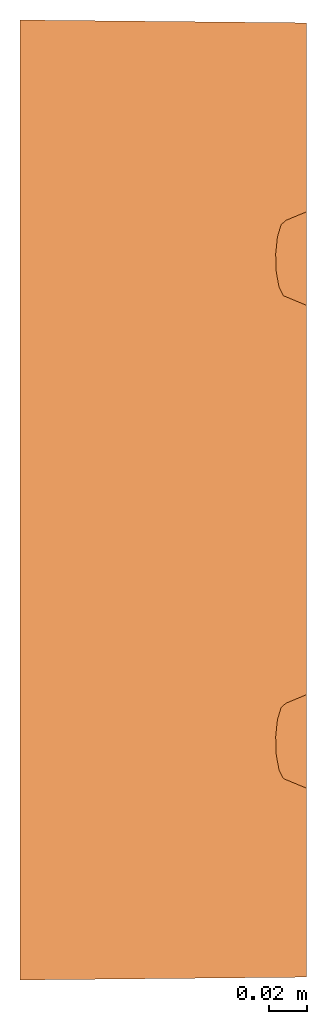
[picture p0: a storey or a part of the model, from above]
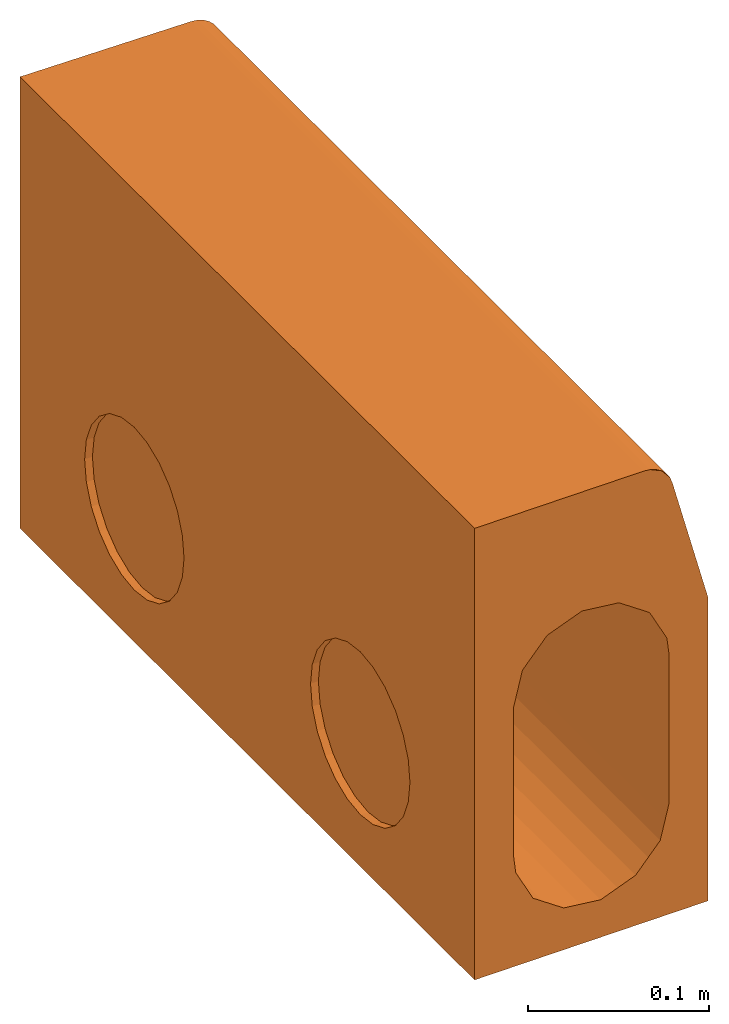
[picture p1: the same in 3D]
Properties of the parts of a building model (IFC2X3)

# File
Description: ViewDefinition [CoordinationView]
File name: 7971 - 25-11m internal mitre.ifc
Time: 2013-09-12T12:57:43
Written by: Autodesk Revit 2013
Made in: 20120221_2030(x64)

# IfcProject, Project Number
LongName: Project Name; Phase: Project Status

# IfcSite, Default
RefLatitude: 42, 21, 30, 344238; RefLongitude: -71, -3, -35, -194702; RefElevation: 0 mm

# IfcBuilding
Pset_BuildingCommon - NumberOfStoreys: 2
Other - Project Address: Enter address here; Client Name: Owner; Project Name: Project Name; Project Number: Project Number; Project Status: Project Status; Project Issue Date: Issue Date

# IfcBuildingStorey (2)
Constraints - Elevation Base: 0
Graphics - Symbol: M_Level Head - Circle: M_Level Head - Circle; Symbol at End 1 Default: no; Line Weight: 1; Symbol at End 2 Default: yes; Line Pattern: Center; Color: 0
Identity Data - Structural: no; Building Story: yes
Dimensions - Computation Height: 0 mm
Name | LongName = Name | Elevation (mm) = Constraints, Elevation (mm)
T.O. Fnd. Wall | T.O. Fnd. Wall | -300
Level 1 | Level 1 | 0

# IfcBuildingElementProxy: 7971 - 25-11m internal mitre, Civil-Drainage-Channel-ACO-KerbDrain-HB305 Part 2:7971 - 25-11m internal mitre:7971 - 25-11m internal mitre:263456
In: T.O. Fnd. Wall
Material: ACO Polymer Concrete.
Other - Revision: 1; CreatedBy: www.aco.co.uk
Construction - KDHB305 1.8m_radius: no; KDHB305 25-11m external_mitre: no; KDHB305 7-6m external_mitre: no; KDHB305_quadrant: no; KDHB305 10-8m_external_mitre: no; KDHB305 25-11m internal_mitre: yes; KDHB305 RH drop kerb-4999: no; KDHB305 6m _external_radius: no; flush drainable centre stone: no; KDHB305 internal_angle: no; LH drop kerb- 6m ext rad: no
Constraints - Moves With Nearby Elements: no; Level: Level: Level 1
Phasing - Phase Created: Phase 1
Dimensions - Volume: 12860259 mm3; Curved RH Void End: -3070 mm; Mite Long Side Length: 497 mm; Curved RH Void Start: -3060 mm; 1.8m Radius Unit void End: -4805 mm; Curved LH Void Start: 3000 mm; Void L End: -3010 mm; Quadrant void End: 2620.7 mm; Void L Start: -3000 mm; Mitre Void Start: 0 mm; mitre small length: 500 mm; Quadrant void Start: 2600.7 mm; Curved LH Void End: 3010 mm; 6m Radius unit void Start: -6000 mm; Straight Void Depth: -7600 mm; 1.8m Radius unit Void Start: -4800 mm; Mitre Void End: -180 mm; Staright Void Depth: -7605 mm; Flush Drainable Centre Stone Void End: -4505 mm; Void_Length: 500 mm; 6m Radius Unit Void end: -6005 mm; Flush Drainable Centre Stone Void Start: -4500 mm; Void_Width: 150 mm
Pset_BuildingElementProxyCommon - Reference: 7971 - 25-11m internal mitre
Data - Drainage Slot Intake area: 14592mm²/m; ACO Hydraulic Design Software: http://www.acodesign.co.uk; Concrete Surround Volume - Load Class A 15 - D 400 - Grass or Asphalt Pavement: N/A; Hydraulic Performance: http://www.aco.co.uk/download.php?id=120; Installation - Concrete Grade: Refer to brochure; Connection Pipe O.D: N/A; Product Standard: BS EN 1433:2002, CE marked, Kitemarked; Drainage Slot Width: 50mm; Concrete Surround Volume - Load Class A 15 - D 400 - Concrete Pavement: N/A; Product Dimensions: 500/503mm x 150mm x 305mm (LxWxH); Invert Depth: 280mm; Product Weight: 26.7 Kg; Load Class: A 15 - D 400; Channel C.S.A: 0.02m²
Identity Data - Cost: 0; OmniClass Number: 23.70.50.24; Address: ACO Business Park, Hitchin Road, Shefford, Bedfordshire, United Kingdom SG17 5TE; Maintenance guidelines: http://www.aco.co.uk/download.php?id=120; e-mail Technical: technical@aco.co.uk; Manufacturer: ACO Technologies plc - ACO Water Management Division; e-mail Sales: customersupport@aco.co.uk; Price: POA - contact ACO; URL: www.aco.co.uk; Type Comments: ACO KerbDrain HB305 half battered 25-11m internal mitre unit 500/503mm long; OmniClass Title: Rainwater Removal; Telephone: +44 (0)1462 816666; Product Page URL: http://www.aco.co.uk/product_detail.php?id=3; Assembly Code: D2040; Installation guidelines: http://www.aco.co.uk/download.php?id=120; Fax: +44 (0)1462 815895; Product Code: 7971; Product brochure: http://www.aco.co.uk/download.php?id=120; Assembly Description: Rain Water Drainage; Model: ACO KerbDrain HB305; Model Description: Combined kerb and drainage system
General - SerialNumber: 0.000000; TagNumber: 0.000000
Green Building Properties - End Cap Recycled Material Content: N/A; Channel Recyclable: Fully recyclable; Access Cover/Frame Recycled Material Content: N/A; End Cap Recyclable: N/A; Access Cover/Frame Recyclable: N/A; Channel Recycled Material Content: 20% minimum
Materials and Finishes - End Cap Colour: N/A; Channel Material: Vienite® Synthetic Resin Concrete; Connection Pipe Material Colour: N/A; Access Cover/Frame Material: N/A; Channel Colour: Grey; Access Cover/Frame Finish: N/A; Connection Pipe Material: N/A; End Cap Material: N/A; Access Cover/Frame Colour: N/A

# IfcOpeningElement: Recess (8)
In: Level 1
Constraints - Room Bounding: yes; Height Offset From Level: 0 mm; Level: Level: Level 1; Related to Mass: no
Dimensions - Perimeter: 21157.2 mm; Area: 27858925 mm2; Thickness: 400 mm; Volume: 11130110635 mm3
Phasing - Phase Created: Phase 1
Structural - Enable Analytical Model: no; Structural: no
Construction - Function: 0; Default Thickness: 400 mm
Analytical Properties - Absorptance: 0.1; Roughness: 1
Graphics - Coarse Scale Fill Color: 0

# IfcSlab: Floor:Generic Floor - 400mm, Floor:Generic Floor - 400mm:184025
In: Level 1
PredefinedType: FLOOR; Material: Default Floor 400 mm
Constraints - Room Bounding: yes; Height Offset From Level: 0 mm; Level: Level: Level 1; Related to Mass: no
Dimensions - Perimeter: 21157.2 mm; Area: 27858925 mm2; Thickness: 400 mm; Volume: 11130110635 mm3
Phasing - Phase Created: Phase 1
Structural - Enable Analytical Model: no; Structural: no
Pset_SlabCommon - Reference: Generic Floor - 400mm; IsExternal: no; LoadBearing: yes
Construction - Function: 0; Default Thickness: 400 mm
Analytical Properties - Absorptance: 0.1; Roughness: 1
Graphics - Coarse Scale Fill Color: 0
